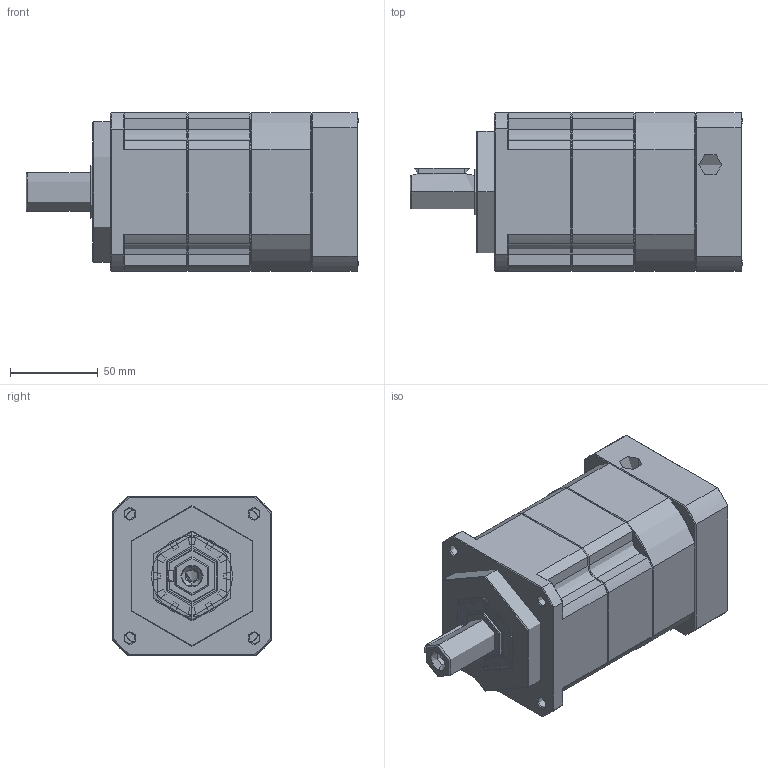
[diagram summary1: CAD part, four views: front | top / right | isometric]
STEP (ISO 10303-21) file: header records copied from the file, then geometry measured from it (millimetres).
FILE_DESCRIPTION (( 'STEP AP214' ), '1' );
FILE_NAME ('ZPB090-D22-L2-P1-14-80-100-M6.step', '2024-06-07T18:20:42', ( 'Windows 蚚誧' ), ( 'Organization' ), 'SwSTEP 2.0', 'SolidWorks 2016', '' );
FILE_SCHEMA (( 'AUTOMOTIVE_DESIGN' ));
Length unit declared in the file: millimetre
Products named in the file (1): ZPB090-D22-L2-P1-14-80-100-M6
Bounding box: 189 x 90 x 90 mm (x, y, z)
Topology: 0 solids, 34 shells, 1898 faces, 5035 edges, 3191 vertices
Faces by surface type: plane 972, bspline 389, cone 291, cylinder 244, torus 2
Full cylindrical faces by diameter (mm): 6.72 x4
Entity records: 96813 total; most frequent: CARTESIAN_POINT 48389, ORIENTED_EDGE 9926, DIRECTION 7708, EDGE_CURVE 4984, VECTOR 3276, LINE 3276, VERTEX_POINT 3160, AXIS2_PLACEMENT_3D 2216
One B-rep face of a CAD part: STEP entity #40060.
In plain terms, the planar face has unit normal (-1, 0, 0).
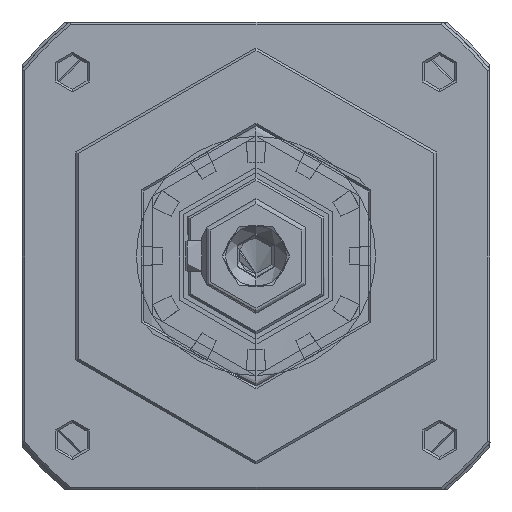
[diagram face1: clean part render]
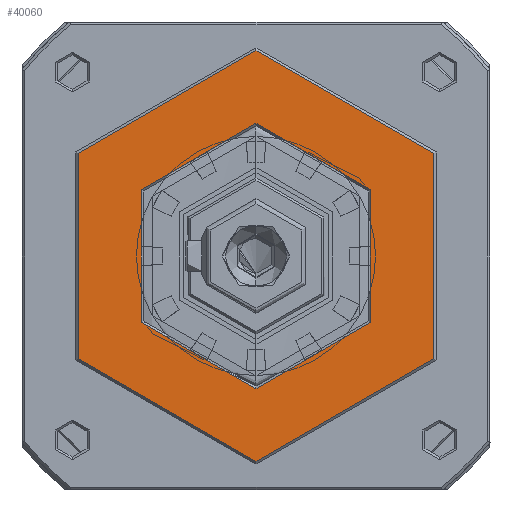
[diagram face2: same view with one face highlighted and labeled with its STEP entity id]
Its self-contained STEP definition (entity closure, numbers rounded to 3 decimals):
#3652 = DIRECTION ( 'NONE',  ( 0., 0., -1. ) ) ;
#8006 = ORIENTED_EDGE ( 'NONE', *, *, #77346, .T. ) ;
#11584 = PLANE ( 'NONE',  #85823 ) ;
#12229 = DIRECTION ( 'NONE',  ( 1., 0., 0. ) ) ;
#20179 = CARTESIAN_POINT ( 'NONE',  ( 0., 0., -25.5 ) ) ;
#20648 = AXIS2_PLACEMENT_3D ( 'NONE', #65156, #35278, #95988 ) ;
#25389 = DIRECTION ( 'NONE',  ( 0., 0., -1. ) ) ;
#27162 = CARTESIAN_POINT ( 'NONE',  ( 0., -39.974, 39.974 ) ) ;
#30553 = VERTEX_POINT ( 'NONE', #20179 ) ;
#30651 = EDGE_CURVE ( 'NONE', #77032, #30553, #88425, .T. ) ;
#33477 = CIRCLE ( 'NONE', #70680, 39.5 ) ;
#34645 = EDGE_LOOP ( 'NONE', ( #66978, #39427 ) ) ;
#35278 = DIRECTION ( 'NONE',  ( 1., 0., 0. ) ) ;
#39427 = ORIENTED_EDGE ( 'NONE', *, *, #44796, .F. ) ;
#39673 = FACE_BOUND ( 'NONE', #87913, .T. ) ;
#40060 = ADVANCED_FACE ( 'NONE', ( #39673, #50340 ), #11584, .F. ) ;
#44796 = EDGE_CURVE ( 'NONE', #67838, #45079, #56912, .T. ) ;
#45079 = VERTEX_POINT ( 'NONE', #47073 ) ;
#45460 = ORIENTED_EDGE ( 'NONE', *, *, #30651, .T. ) ;
#47073 = CARTESIAN_POINT ( 'NONE',  ( 0., 0., -39.5 ) ) ;
#47954 = DIRECTION ( 'NONE',  ( 1., 0., 0. ) ) ;
#49002 = DIRECTION ( 'NONE',  ( 0., 0., 1. ) ) ;
#50340 = FACE_OUTER_BOUND ( 'NONE', #34645, .T. ) ;
#54022 = AXIS2_PLACEMENT_3D ( 'NONE', #90634, #83991, #68804 ) ;
#56338 = DIRECTION ( 'NONE',  ( 1., 0., 0. ) ) ;
#56912 = CIRCLE ( 'NONE', #54022, 39.5 ) ;
#65156 = CARTESIAN_POINT ( 'NONE',  ( 0., 0., 0. ) ) ;
#66978 = ORIENTED_EDGE ( 'NONE', *, *, #94508, .F. ) ;
#67838 = VERTEX_POINT ( 'NONE', #68376 ) ;
#67965 = CIRCLE ( 'NONE', #88084, 25.5 ) ;
#68376 = CARTESIAN_POINT ( 'NONE',  ( 0., 0., 39.5 ) ) ;
#68804 = DIRECTION ( 'NONE',  ( 0., 0., -1. ) ) ;
#70080 = CARTESIAN_POINT ( 'NONE',  ( 0., 0., 25.5 ) ) ;
#70680 = AXIS2_PLACEMENT_3D ( 'NONE', #93737, #47954, #25389 ) ;
#77032 = VERTEX_POINT ( 'NONE', #70080 ) ;
#77346 = EDGE_CURVE ( 'NONE', #30553, #77032, #67965, .T. ) ;
#83991 = DIRECTION ( 'NONE',  ( 1., 0., 0. ) ) ;
#85823 = AXIS2_PLACEMENT_3D ( 'NONE', #27162, #12229, #3652 ) ;
#87913 = EDGE_LOOP ( 'NONE', ( #45460, #8006 ) ) ;
#88084 = AXIS2_PLACEMENT_3D ( 'NONE', #94123, #56338, #49002 ) ;
#88425 = CIRCLE ( 'NONE', #20648, 25.5 ) ;
#90634 = CARTESIAN_POINT ( 'NONE',  ( 0., 0., 0. ) ) ;
#93737 = CARTESIAN_POINT ( 'NONE',  ( 0., 0., 0. ) ) ;
#94123 = CARTESIAN_POINT ( 'NONE',  ( 0., 0., 0. ) ) ;
#94508 = EDGE_CURVE ( 'NONE', #45079, #67838, #33477, .T. ) ;
#95988 = DIRECTION ( 'NONE',  ( 0., 0., 1. ) ) ;
